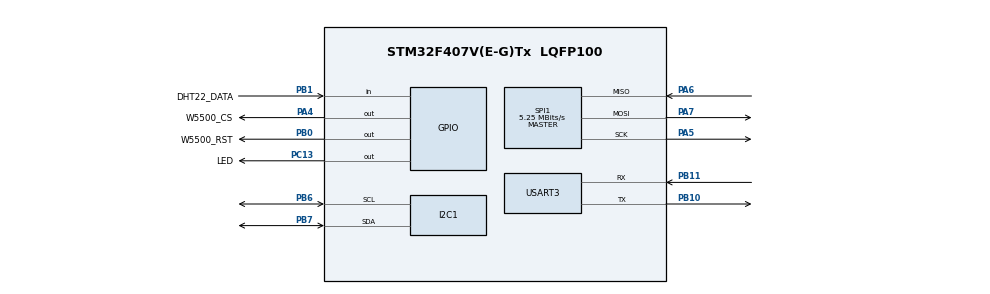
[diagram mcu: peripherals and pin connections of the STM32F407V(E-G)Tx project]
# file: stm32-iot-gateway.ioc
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FREERTOS.Tasks01=SensorTask,24,256,vSensorTask,Default,NULL,Dynamic,NULL,NULL;DisplayTask,16,256,vDisplayTask,Default,NULL,Dynamic,NULL,NULL;NetworkTask,32,1024,vNetworkTask,Default,NULL,Dynamic,NULL,NULL;LEDTask,8,128,VLEDTask,Default,NULL,Dynamic,NULL,NULL
FREERTOS.configCHECK_FOR_STACK_OVERFLOW=2
FREERTOS.configMAX_TASK_NAME_LEN=16
FREERTOS.configTOTAL_HEAP_SIZE=30720
Mcu.Family=STM32F4
Mcu.Name=STM32F407V(E-G)Tx
Mcu.Package=LQFP100
NVIC.PriorityGroup=NVIC_PRIORITYGROUP_4
NVIC.TIM6_DAC_IRQn=true\:15\:0\:false\:false\:true\:false\:false\:true\:true
NVIC.TimeBase=TIM6_DAC_IRQn
NVIC.TimeBaseIP=TIM6
PA13.Mode=Serial_Wire
PA13.Signal=SYS_JTMS-SWDIO
PA14.Mode=Serial_Wire
PA14.Signal=SYS_JTCK-SWCLK
PA4.GPIO_Label=W5500_CS
PA4.Signal=GPIO_Output
PA5.Mode=Full_Duplex_Master
PA5.Signal=SPI1_SCK
PA6.Mode=Full_Duplex_Master
PA6.Signal=SPI1_MISO
PA7.Mode=Full_Duplex_Master
PA7.Signal=SPI1_MOSI
PB0.GPIO_Label=W5500_RST
PB0.Signal=GPIO_Output
PB1.GPIO_Label=DHT22_DATA
PB1.Signal=GPIO_Input
PB10.Mode=Asynchronous
PB10.Signal=USART3_TX
PB11.Mode=Asynchronous
PB11.Signal=USART3_RX
PB6.Mode=I2C
PB6.Signal=I2C1_SCL
PB7.Mode=I2C
PB7.Signal=I2C1_SDA
PC13-ANTI_TAMP.GPIO_Label=LED
PC13-ANTI_TAMP.Signal=GPIO_Output
PH0-OSC_IN.Mode=HSE-External-Oscillator
PH0-OSC_IN.Signal=RCC_OSC_IN
PH1-OSC_OUT.Mode=HSE-External-Oscillator
PH1-OSC_OUT.Signal=RCC_OSC_OUT
ProjectManager.HeapSize=0x200
ProjectManager.StackSize=0x400
ProjectManager.TargetToolchain=CMake
RCC.48MHZClocksFreq_Value=84000000
RCC.AHBFreq_Value=168000000
RCC.APB1CLKDivider=RCC_HCLK_DIV4
RCC.APB1Freq_Value=42000000
RCC.APB1TimFreq_Value=84000000
RCC.APB2CLKDivider=RCC_HCLK_DIV2
RCC.APB2Freq_Value=84000000
RCC.APB2TimFreq_Value=168000000
RCC.CortexFreq_Value=168000000
RCC.HCLKFreq_Value=168000000
RCC.HSE_VALUE=8000000
RCC.HSI_VALUE=16000000
RCC.PLLM=8
RCC.PLLN=336
RCC.PLLSourceVirtual=RCC_PLLSOURCE_HSE
RCC.SYSCLKFreq_VALUE=168000000
RCC.SYSCLKSource=RCC_SYSCLKSOURCE_PLLCLK
RCC.VCOOutputFreq_Value=336000000
SPI1.BaudRatePrescaler=SPI_BAUDRATEPRESCALER_16
SPI1.CalculateBaudRate=5.25 MBits/s
SPI1.Direction=SPI_DIRECTION_2LINES
SPI1.Mode=SPI_MODE_MASTER
SPI1.VirtualType=VM_MASTER
USART3.VirtualMode=VM_ASYNC
VP_FREERTOS_VS_CMSIS_V2.Mode=CMSIS_V2
VP_SYS_VS_tim6.Mode=TIM6
board=custom

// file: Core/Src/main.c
/* USER CODE BEGIN Header */
/**
  ******************************************************************************
  * @file           : main.c
  * @brief          : Main program body
  ******************************************************************************
  */
/* USER CODE END Header */
#include "main.h"
#include "cmsis_os.h"
#include "i2c.h"
#include "spi.h"
#include "usart.h"
#include "gpio.h"

/* USER CODE BEGIN Includes */
#include <stdio.h>
#include <string.h>
/* USER CODE END Includes */

void SystemClock_Config(void);
void MX_FREERTOS_Init(void);

int main(void)
{
  HAL_Init();
  SystemClock_Config();
  MX_GPIO_Init();
  MX_I2C1_Init();
  MX_SPI1_Init();
  MX_USART3_UART_Init();

  /* USER CODE BEGIN 2 */
  HAL_UART_Transmit(&huart3, (uint8_t *)"BOOT OK\r\n", 9, 100);
  /* USER CODE END 2 */

  /* Call init function for freertos objects (in freertos.c) */
  MX_FREERTOS_Init();

  /* Start scheduler */
  osKernelStart();

  /* 不应到这里 */
  while (1) {}

  /* Start scheduler */
  osKernelStart();

  /* We should never get here as control is now taken by the scheduler */

  /* Infinite loop */
  while (1)
  {

  }
}

void SystemClock_Config(void)
{
  RCC_OscInitTypeDef RCC_OscInitStruct = {0};
  RCC_ClkInitTypeDef RCC_ClkInitStruct = {0};

  __HAL_RCC_PWR_CLK_ENABLE();
  __HAL_PWR_VOLTAGESCALING_CONFIG(PWR_REGULATOR_VOLTAGE_SCALE1);

  /* 配置 HSE + PLL: 8MHz HSE → PLL → 168MHz SYSCLK */
  RCC_OscInitStruct.OscillatorType = RCC_OSCILLATORTYPE_HSE;
  RCC_OscInitStruct.HSEState = RCC_HSE_ON;
  RCC_OscInitStruct.PLL.PLLState = RCC_PLL_ON;
  RCC_OscInitStruct.PLL.PLLSource = RCC_PLLSOURCE_HSE;
  RCC_OscInitStruct.PLL.PLLM = 8;
  RCC_OscInitStruct.PLL.PLLN = 336;
  RCC_OscInitStruct.PLL.PLLP = RCC_PLLP_DIV2;
  RCC_OscInitStruct.PLL.PLLQ = 4;
  if (HAL_RCC_OscConfig(&RCC_OscInitStruct) != HAL_OK)
  {
    /* HSE 启动失败，回退到 HSI 16MHz */
    RCC_OscInitStruct.OscillatorType = RCC_OSCILLATORTYPE_HSI;
    RCC_OscInitStruct.HSIState = RCC_HSI_ON;
    RCC_OscInitStruct.PLL.PLLState = RCC_PLL_OFF;
    HAL_RCC_OscConfig(&RCC_OscInitStruct);

    RCC_ClkInitStruct.ClockType = RCC_CLOCKTYPE_HCLK|RCC_CLOCKTYPE_SYSCLK
                                |RCC_CLOCKTYPE_PCLK1|RCC_CLOCKTYPE_PCLK2;
    RCC_ClkInitStruct.SYSCLKSource = RCC_SYSCLKSOURCE_HSI;
    RCC_ClkInitStruct.AHBCLKDivider = RCC_SYSCLK_DIV1;
    RCC_ClkInitStruct.APB1CLKDivider = RCC_HCLK_DIV1;
    RCC_ClkInitStruct.APB2CLKDivider = RCC_HCLK_DIV1;
    HAL_RCC_ClockConfig(&RCC_ClkInitStruct, FLASH_LATENCY_0);
    /* 必须更新 SystemCoreClock，否则后续外设波特率计算错误 */
    SystemCoreClockUpdate();
    return;
  }

  /* 配置总线分频: HCLK=168MHz, APB1=42MHz, APB2=84MHz */
  RCC_ClkInitStruct.ClockType = RCC_CLOCKTYPE_HCLK|RCC_CLOCKTYPE_SYSCLK
                              |RCC_CLOCKTYPE_PCLK1|RCC_CLOCKTYPE_PCLK2;
  RCC_ClkInitStruct.SYSCLKSource = RCC_SYSCLKSOURCE_PLLCLK;
  RCC_ClkInitStruct.AHBCLKDivider = RCC_SYSCLK_DIV1;
  RCC_ClkInitStruct.APB1CLKDivider = RCC_HCLK_DIV4;
  RCC_ClkInitStruct.APB2CLKDivider = RCC_HCLK_DIV2;
  if (HAL_RCC_ClockConfig(&RCC_ClkInitStruct, FLASH_LATENCY_5) != HAL_OK)
  {
    Error_Handler();
  }
}

void HAL_TIM_PeriodElapsedCallback(TIM_HandleTypeDef *htim)
{
  if (htim->Instance == TIM6)
  {
    HAL_IncTick();
  }
}

void Error_Handler(void)
{
  __disable_irq();
  while (1) {}
}

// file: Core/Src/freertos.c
/* USER CODE BEGIN Header */
/**
  ******************************************************************************
  * File Name          : freertos.c
  * Description        : Code for freertos applications
  ******************************************************************************
  * @attention
  *
  * Copyright (c) 2026 STMicroelectronics.
  * All rights reserved.
  *
  * This software is licensed under terms that can be found in the LICENSE file
  * in the root directory of this software component.
  * If no LICENSE file comes with this software, it is provided AS-IS.
  *
  ******************************************************************************
  */
/* USER CODE END Header */

#include "FreeRTOS.h"
#include "task.h"
#include "main.h"
#include "cmsis_os.h"

/* USER CODE BEGIN Includes */
#include "dht22.h"
#include "OLED.h"
#include "w5500.h"
#include <stdio.h>
#include <string.h>
/* USER CODE END Includes */

/* USER CODE BEGIN Variables */
/* 共享传感器数据 (由 SensorTask 写入，其他任务读取) */
DHT22_Data g_sensor_data = {0};
osMutexId_t g_sensor_mutex = NULL;

/* 网络状态 (由 NetworkTask 写入，DisplayTask 读取) */
volatile uint8_t g_net_status = 0;  /* 0=INIT 1=LINK 2=CONNECTING 3=CONNECTED 4=FAIL */
/* USER CODE END Variables */
/* Definitions for SensorTask */
osThreadId_t SensorTaskHandle;
const osThreadAttr_t SensorTask_attributes = {
  .name = "SensorTask",
  .stack_size = 256 * 4,
  .priority = (osPriority_t) osPriorityNormal,
};
/* Definitions for DisplayTask */
osThreadId_t DisplayTaskHandle;
const osThreadAttr_t DisplayTask_attributes = {
  .name = "DisplayTask",
  .stack_size = 256 * 4,
  .priority = (osPriority_t) osPriorityBelowNormal,
};
/* Definitions for NetworkTask */
osThreadId_t NetworkTaskHandle;
const osThreadAttr_t NetworkTask_attributes = {
  .name = "NetworkTask",
  .stack_size = 1024 * 4,
  .priority = (osPriority_t) osPriorityAboveNormal,
};
/* USER CODE BEGIN Variables2 */
extern I2C_HandleTypeDef hi2c1;
extern UART_HandleTypeDef huart3;
/* USER CODE END Variables2 */

void vSensorTask(void *argument);
void vDisplayTask(void *argument);
void vNetworkTask(void *argument);

void MX_FREERTOS_Init(void); /* (MISRA C 2004 rule 8.1) */

/* Hook prototypes */
void vApplicationStackOverflowHook(xTaskHandle xTask, signed char *pcTaskName);

/* USER CODE BEGIN 4 */
void vApplicationStackOverflowHook(xTaskHandle xTask, signed char *pcTaskName)
{
   /* Run time stack overflow checking is performed if
   configCHECK_FOR_STACK_OVERFLOW is defined to 1 or 2. This hook function is
   called if a stack overflow is detected. */
}
/* USER CODE END 4 */

void MX_FREERTOS_Init(void) {
  /* USER CODE BEGIN Init */
  osKernelInitialize();
  /* USER CODE END Init */

  /* USER CODE BEGIN RTOS_MUTEX */
  const osMutexAttr_t sensor_mutex_attr = {
    .name = "SensorMutex"
  };
  g_sensor_mutex = osMutexNew(&sensor_mutex_attr);
  /* USER CODE END RTOS_MUTEX */

  /* Create the thread(s) */
  /* creation of SensorTask */
  SensorTaskHandle = osThreadNew(vSensorTask, NULL, &SensorTask_attributes);

  /* creation of DisplayTask */
  DisplayTaskHandle = osThreadNew(vDisplayTask, NULL, &DisplayTask_attributes);

  /* creation of NetworkTask */
  NetworkTaskHandle = osThreadNew(vNetworkTask, NULL, &NetworkTask_attributes);

}

void vSensorTask(void *argument)
{
  /* USER CODE BEGIN vSensorTask */
  /* 初始化 DWT 延时系统 */
  DHT22_Init();

  DHT22_Data local_data;
  DHT22_Status status;
  char buf[64];

  /* Infinite loop */
  for(;;)
  {
    status = DHT22_Read(&local_data);

    if (status == DHT22_OK) {
      /* 读取成功，更新共享数据 */
      if (osMutexAcquire(g_sensor_mutex, 100) == osOK) {
        g_sensor_data = local_data;
        osMutexRelease(g_sensor_mutex);
      }

      /* 串口输出: 用整数避免 float 格式化问题 */
      int t = (int)(local_data.temperature * 10);
      int h = (int)(local_data.humidity * 10);
      int t_int = t / 10, t_dec = (t < 0 ? -t : t) % 10;
      int h_int = h / 10, h_dec = (h < 0 ? -h : h) % 10;
      snprintf(buf, sizeof(buf), "T:%d.%d H:%d.%d\r\n", t_int, t_dec, h_int, h_dec);
      HAL_UART_Transmit(&huart3, (uint8_t*)buf, strlen(buf), 100);
    } else {
      snprintf(buf, sizeof(buf), "ERR:%d\r\n", (int)status);
      HAL_UART_Transmit(&huart3, (uint8_t*)buf, strlen(buf), 100);
    }

    /* 采样间隔 2s */
    osDelay(2000);
  }
  /* USER CODE END vSensorTask */
}

void vDisplayTask(void *argument)
{
  /* USER CODE BEGIN vDisplayTask */
  OLED_Init();

  OLED_ShowString(1, 1, "IoT Gateway");
  OLED_ShowString(2, 1, "NET:");
  OLED_ShowString(3, 1, "Temp:");
  OLED_ShowString(4, 1, "Humi:");

  DHT22_Data local;
  const char *net_str[] = {"INIT", "LINK", "CONNECT..", "CONNECTED", "FAIL"};

  for(;;)
  {
    /* 更新网络状态 (Line 2, Column 5 起) */
    OLED_ShowString(2, 5, "          ");
    OLED_ShowString(2, 5, (char *)net_str[g_net_status]);

    /* 读取共享数据 */
    if (osMutexAcquire(g_sensor_mutex, 100) == osOK) {
      local = g_sensor_data;
      osMutexRelease(g_sensor_mutex);
    }

    /* 更新温度 (Line 3, Column 6 起) */
    OLED_ShowString(3, 6, "         ");
    if (local.valid) {
      int t = (int)(local.temperature * 10);
      char t_buf[8];
      t_buf[0] = (t < 0) ? '-' : ' ';
      int abs_t = (t < 0) ? -t : t;
      t_buf[1] = '0' + abs_t / 100;
      t_buf[2] = '0' + (abs_t / 10) % 10;
      t_buf[3] = '.';
      t_buf[4] = '0' + abs_t % 10;
      t_buf[5] = 'C';
      t_buf[6] = '\0';
      OLED_ShowString(3, 6, t_buf);
    } else {
      OLED_ShowString(3, 6, "--.- C");
    }

    /* 更新湿度 (Line 4, Column 6 起) */
    OLED_ShowString(4, 6, "         ");
    if (local.valid) {
      int h = (int)(local.humidity * 10);
      char h_buf[8];
      int abs_h = (h < 0) ? -h : h;
      h_buf[0] = '0' + abs_h / 100;
      h_buf[1] = '0' + (abs_h / 10) % 10;
      h_buf[2] = '.';
      h_buf[3] = '0' + abs_h % 10;
      h_buf[4] = '%';
      h_buf[5] = '\0';
      OLED_ShowString(4, 6, h_buf);
    } else {
      OLED_ShowString(4, 6, "--.- %");
    }

    osDelay(1000);
  }
  /* USER CODE END vDisplayTask */
}

void vNetworkTask(void *argument)
{
  /* USER CODE BEGIN vNetworkTask */
  char buf[64];
  int len;

  /* ---- 网络配置 ---- */
  #define SOCK_TCP       0
  #define SERVER_IP      192, 168, 1, 1    /* 上位机 IP */
  #define SERVER_PORT    5000               /* 上位机端口 */
  #define REPORT_INTERVAL 5000             /* 上报间隔 5s */

  W5500_Config net = {
    .mac    = {0x02, 0x08, 0xDC, 0x01, 0x02, 0x03},
    .ip     = {192, 168, 1, 100},
    .subnet = {255, 255, 255, 0},
    .gateway= {192, 168, 1, 1},
  };

  const uint8_t server_ip[] = {SERVER_IP};

  /* 初始化 W5500 */
  if (!W5500_Init(&net)) {
    g_net_status = 4;  /* FAIL */
    len = snprintf(buf, sizeof(buf), "W5500 INIT FAIL\r\n");
    HAL_UART_Transmit(&huart3, (uint8_t *)buf, len, 100);
    for (;;) osDelay(1000);
  }

  len = snprintf(buf, sizeof(buf), "W5500 OK v=0x%02X\r\n", W5500_GetVersion());
  HAL_UART_Transmit(&huart3, (uint8_t *)buf, len, 100);

  /* 等待 PHY 链路建立 */
  for (int i = 0; i < 50; i++) {
    if (W5500_GetPHYStatus())
      break;
    osDelay(100);
  }

  if (W5500_GetPHYStatus()) {
    g_net_status = 1;  /* LINK */
    len = snprintf(buf, sizeof(buf), "LINK UP %d.%d.%d.%d\r\n",
                   net.ip[0], net.ip[1], net.ip[2], net.ip[3]);
  } else {
    g_net_status = 4;  /* FAIL */
    len = snprintf(buf, sizeof(buf), "LINK DOWN\r\n");
  }
  HAL_UART_Transmit(&huart3, (uint8_t *)buf, len, 100);

  /* ---- TCP Client 主循环: 连接上位机并定时上报 ---- */
  for(;;)
  {
    /* 1. 打开 Socket */
    if (!W5500_TCP_Open(SOCK_TCP, 0)) {   /* 本地端口 0 = 随机分配 */
      osDelay(1000);
      continue;
    }

    /* 2. 连接上位机 */
    g_net_status = 2;  /* CONNECTING */
    len = snprintf(buf, sizeof(buf), "CONNECTING %d.%d.%d.%d:%d\r\n",
                   server_ip[0], server_ip[1], server_ip[2], server_ip[3],
                   SERVER_PORT);
    HAL_UART_Transmit(&huart3, (uint8_t *)buf, len, 100);

    if (!W5500_TCP_Connect(SOCK_TCP, server_ip, SERVER_PORT)) {
      len = snprintf(buf, sizeof(buf), "CONNECT FAIL, RETRY\r\n");
      HAL_UART_Transmit(&huart3, (uint8_t *)buf, len, 100);
      W5500_TCP_Close(SOCK_TCP);
      osDelay(3000);
      continue;
    }

    g_net_status = 3;  /* CONNECTED */
    len = snprintf(buf, sizeof(buf), "CONNECTED\r\n");
    HAL_UART_Transmit(&huart3, (uint8_t *)buf, len, 100);

    /* 3. 连接成功，定时上报温湿度 */
    while (1)
    {
      uint8_t sr = W5500_GetSocketStatus(SOCK_TCP);

      /* 检查连接是否断开 */
      if (sr == W5500_Sn_SR_CLOSE_WAIT || sr == W5500_Sn_SR_CLOSED) {
        g_net_status = 2;  /* 回到 CONNECTING */
        len = snprintf(buf, sizeof(buf), "DISCONNECTED\r\n");
        HAL_UART_Transmit(&huart3, (uint8_t *)buf, len, 100);
        W5500_TCP_Close(SOCK_TCP);
        break;  /* 跳出重连 */
      }

      /* 读取传感器数据 */
      DHT22_Data d = {0};
      if (osMutexAcquire(g_sensor_mutex, 100) == osOK) {
        d = g_sensor_data;
        osMutexRelease(g_sensor_mutex);
      }

      /* 组装并发送 */
      if (d.valid) {
        int t = (int)(d.temperature * 10);
        int h = (int)(d.humidity * 10);
        len = snprintf(buf, sizeof(buf), "T:%d.%d H:%d.%d\r\n",
                       t/10, (t<0?-t:t)%10, h/10, h%10);
      } else {
        len = snprintf(buf, sizeof(buf), "SENSOR N/A\r\n");
      }

      uint16_t sent = W5500_TCP_Send(SOCK_TCP, (uint8_t *)buf, len);
      if (sent == 0) {
        len = snprintf(buf, sizeof(buf), "SEND FAIL\r\n");
        HAL_UART_Transmit(&huart3, (uint8_t *)buf, len, 100);
      }

      osDelay(REPORT_INTERVAL);
    }
  }
  /* USER CODE END vNetworkTask */
}
